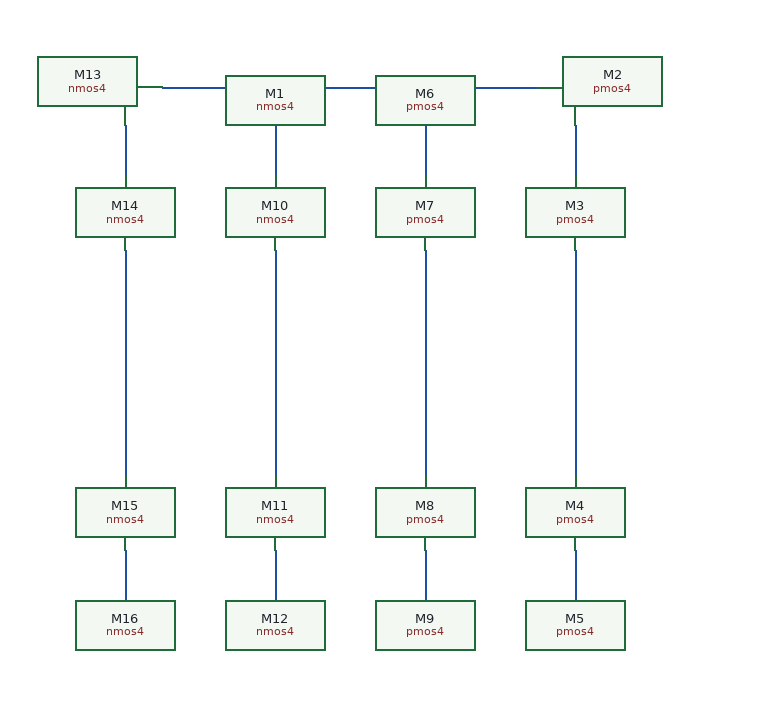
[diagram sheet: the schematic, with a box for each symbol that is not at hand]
v {xschem version=3.4.8RC file_version=1.3}
G {}
K {}
V {}
S {}
F {}
E {}
N 500 -180 500 -140 {lab=#net1}
N 500 -80 500 100 {lab=#net2}
N 500 160 500 200 {lab=#net3}
N 380 160 380 200 {lab=#net4}
N 380 -80 380 100 {lab=#net5}
N 380 -180 380 -140 {lab=#net6}
N 260 -180 260 -140 {lab=#net7}
N 260 -80 260 100 {lab=#net8}
N 260 160 260 200 {lab=#net9}
N 140 160 140 200 {lab=#net10}
N 140 -80 140 100 {lab=#net11}
N 140 -180 140 -140 {lab=#net12}
N 350 -210 470 -210 {lab=#net13}
N 290 -210 350 -210 {lab=#net13}
N 170 -210 290 -210 {lab=#net13}
C {madvlsi/nmos4.sym} 260 -210 2 0 {name=M1
L=0.15
W=1
nf=1 
mult=1
ad="'int((nf+1)/2) * W/nf * 0.29'" 
pd="'2*int((nf+1)/2) * (W/nf + 0.29)'"
as="'int((nf+2)/2) * W/nf * 0.29'" 
ps="'2*int((nf+2)/2) * (W/nf + 0.29)'"
nrd="'0.29 / W'" nrs="'0.29 / W'"
sa=0 sb=0 sd=0
model=nfet_01v8
spiceprefix=X
}
C {madvlsi/pmos4.sym} 500 -210 0 0 {name=M2
L=0.15
W=1
nf=1
mult=1
ad="'int((nf+1)/2) * W/nf * 0.29'" 
pd="'2*int((nf+1)/2) * (W/nf + 0.29)'"
as="'int((nf+2)/2) * W/nf * 0.29'" 
ps="'2*int((nf+2)/2) * (W/nf + 0.29)'"
nrd="'0.29 / W'" nrs="'0.29 / W'"
sa=0 sb=0 sd=0
model=pfet_01v8
spiceprefix=X
}
C {madvlsi/pmos4.sym} 500 -110 0 0 {name=M3
L=0.15
W=1
nf=1
mult=1
ad="'int((nf+1)/2) * W/nf * 0.29'" 
pd="'2*int((nf+1)/2) * (W/nf + 0.29)'"
as="'int((nf+2)/2) * W/nf * 0.29'" 
ps="'2*int((nf+2)/2) * (W/nf + 0.29)'"
nrd="'0.29 / W'" nrs="'0.29 / W'"
sa=0 sb=0 sd=0
model=pfet_01v8
spiceprefix=X
}
C {madvlsi/pmos4.sym} 500 130 0 0 {name=M4
L=0.15
W=1
nf=1
mult=1
ad="'int((nf+1)/2) * W/nf * 0.29'" 
pd="'2*int((nf+1)/2) * (W/nf + 0.29)'"
as="'int((nf+2)/2) * W/nf * 0.29'" 
ps="'2*int((nf+2)/2) * (W/nf + 0.29)'"
nrd="'0.29 / W'" nrs="'0.29 / W'"
sa=0 sb=0 sd=0
model=pfet_01v8
spiceprefix=X
}
C {madvlsi/pmos4.sym} 500 230 0 0 {name=M5
L=0.15
W=1
nf=1
mult=1
ad="'int((nf+1)/2) * W/nf * 0.29'" 
pd="'2*int((nf+1)/2) * (W/nf + 0.29)'"
as="'int((nf+2)/2) * W/nf * 0.29'" 
ps="'2*int((nf+2)/2) * (W/nf + 0.29)'"
nrd="'0.29 / W'" nrs="'0.29 / W'"
sa=0 sb=0 sd=0
model=pfet_01v8
spiceprefix=X
}
C {madvlsi/pmos4.sym} 380 -210 0 0 {name=M6
L=0.15
W=1
nf=1
mult=1
ad="'int((nf+1)/2) * W/nf * 0.29'" 
pd="'2*int((nf+1)/2) * (W/nf + 0.29)'"
as="'int((nf+2)/2) * W/nf * 0.29'" 
ps="'2*int((nf+2)/2) * (W/nf + 0.29)'"
nrd="'0.29 / W'" nrs="'0.29 / W'"
sa=0 sb=0 sd=0
model=pfet_01v8
spiceprefix=X
}
C {madvlsi/pmos4.sym} 380 -110 0 0 {name=M7
L=0.15
W=1
nf=1
mult=1
ad="'int((nf+1)/2) * W/nf * 0.29'" 
pd="'2*int((nf+1)/2) * (W/nf + 0.29)'"
as="'int((nf+2)/2) * W/nf * 0.29'" 
ps="'2*int((nf+2)/2) * (W/nf + 0.29)'"
nrd="'0.29 / W'" nrs="'0.29 / W'"
sa=0 sb=0 sd=0
model=pfet_01v8
spiceprefix=X
}
C {madvlsi/pmos4.sym} 380 130 0 0 {name=M8
L=0.15
W=1
nf=1
mult=1
ad="'int((nf+1)/2) * W/nf * 0.29'" 
pd="'2*int((nf+1)/2) * (W/nf + 0.29)'"
as="'int((nf+2)/2) * W/nf * 0.29'" 
ps="'2*int((nf+2)/2) * (W/nf + 0.29)'"
nrd="'0.29 / W'" nrs="'0.29 / W'"
sa=0 sb=0 sd=0
model=pfet_01v8
spiceprefix=X
}
C {madvlsi/pmos4.sym} 380 230 0 0 {name=M9
L=0.15
W=1
nf=1
mult=1
ad="'int((nf+1)/2) * W/nf * 0.29'" 
pd="'2*int((nf+1)/2) * (W/nf + 0.29)'"
as="'int((nf+2)/2) * W/nf * 0.29'" 
ps="'2*int((nf+2)/2) * (W/nf + 0.29)'"
nrd="'0.29 / W'" nrs="'0.29 / W'"
sa=0 sb=0 sd=0
model=pfet_01v8
spiceprefix=X
}
C {madvlsi/nmos4.sym} 260 -110 2 0 {name=M10
L=0.15
W=1
nf=1 
mult=1
ad="'int((nf+1)/2) * W/nf * 0.29'" 
pd="'2*int((nf+1)/2) * (W/nf + 0.29)'"
as="'int((nf+2)/2) * W/nf * 0.29'" 
ps="'2*int((nf+2)/2) * (W/nf + 0.29)'"
nrd="'0.29 / W'" nrs="'0.29 / W'"
sa=0 sb=0 sd=0
model=nfet_01v8
spiceprefix=X
}
C {madvlsi/nmos4.sym} 260 130 2 0 {name=M11
L=0.15
W=1
nf=1 
mult=1
ad="'int((nf+1)/2) * W/nf * 0.29'" 
pd="'2*int((nf+1)/2) * (W/nf + 0.29)'"
as="'int((nf+2)/2) * W/nf * 0.29'" 
ps="'2*int((nf+2)/2) * (W/nf + 0.29)'"
nrd="'0.29 / W'" nrs="'0.29 / W'"
sa=0 sb=0 sd=0
model=nfet_01v8
spiceprefix=X
}
C {madvlsi/nmos4.sym} 260 230 2 0 {name=M12
L=0.15
W=1
nf=1 
mult=1
ad="'int((nf+1)/2) * W/nf * 0.29'" 
pd="'2*int((nf+1)/2) * (W/nf + 0.29)'"
as="'int((nf+2)/2) * W/nf * 0.29'" 
ps="'2*int((nf+2)/2) * (W/nf + 0.29)'"
nrd="'0.29 / W'" nrs="'0.29 / W'"
sa=0 sb=0 sd=0
model=nfet_01v8
spiceprefix=X
}
C {madvlsi/nmos4.sym} 140 -210 2 0 {name=M13
L=0.15
W=1
nf=1 
mult=1
ad="'int((nf+1)/2) * W/nf * 0.29'" 
pd="'2*int((nf+1)/2) * (W/nf + 0.29)'"
as="'int((nf+2)/2) * W/nf * 0.29'" 
ps="'2*int((nf+2)/2) * (W/nf + 0.29)'"
nrd="'0.29 / W'" nrs="'0.29 / W'"
sa=0 sb=0 sd=0
model=nfet_01v8
spiceprefix=X
}
C {madvlsi/nmos4.sym} 140 -110 2 0 {name=M14
L=0.15
W=1
nf=1 
mult=1
ad="'int((nf+1)/2) * W/nf * 0.29'" 
pd="'2*int((nf+1)/2) * (W/nf + 0.29)'"
as="'int((nf+2)/2) * W/nf * 0.29'" 
ps="'2*int((nf+2)/2) * (W/nf + 0.29)'"
nrd="'0.29 / W'" nrs="'0.29 / W'"
sa=0 sb=0 sd=0
model=nfet_01v8
spiceprefix=X
}
C {madvlsi/nmos4.sym} 140 130 2 0 {name=M15
L=0.15
W=1
nf=1 
mult=1
ad="'int((nf+1)/2) * W/nf * 0.29'" 
pd="'2*int((nf+1)/2) * (W/nf + 0.29)'"
as="'int((nf+2)/2) * W/nf * 0.29'" 
ps="'2*int((nf+2)/2) * (W/nf + 0.29)'"
nrd="'0.29 / W'" nrs="'0.29 / W'"
sa=0 sb=0 sd=0
model=nfet_01v8
spiceprefix=X
}
C {madvlsi/nmos4.sym} 140 230 2 0 {name=M16
L=0.15
W=1
nf=1 
mult=1
ad="'int((nf+1)/2) * W/nf * 0.29'" 
pd="'2*int((nf+1)/2) * (W/nf + 0.29)'"
as="'int((nf+2)/2) * W/nf * 0.29'" 
ps="'2*int((nf+2)/2) * (W/nf + 0.29)'"
nrd="'0.29 / W'" nrs="'0.29 / W'"
sa=0 sb=0 sd=0
model=nfet_01v8
spiceprefix=X
}
